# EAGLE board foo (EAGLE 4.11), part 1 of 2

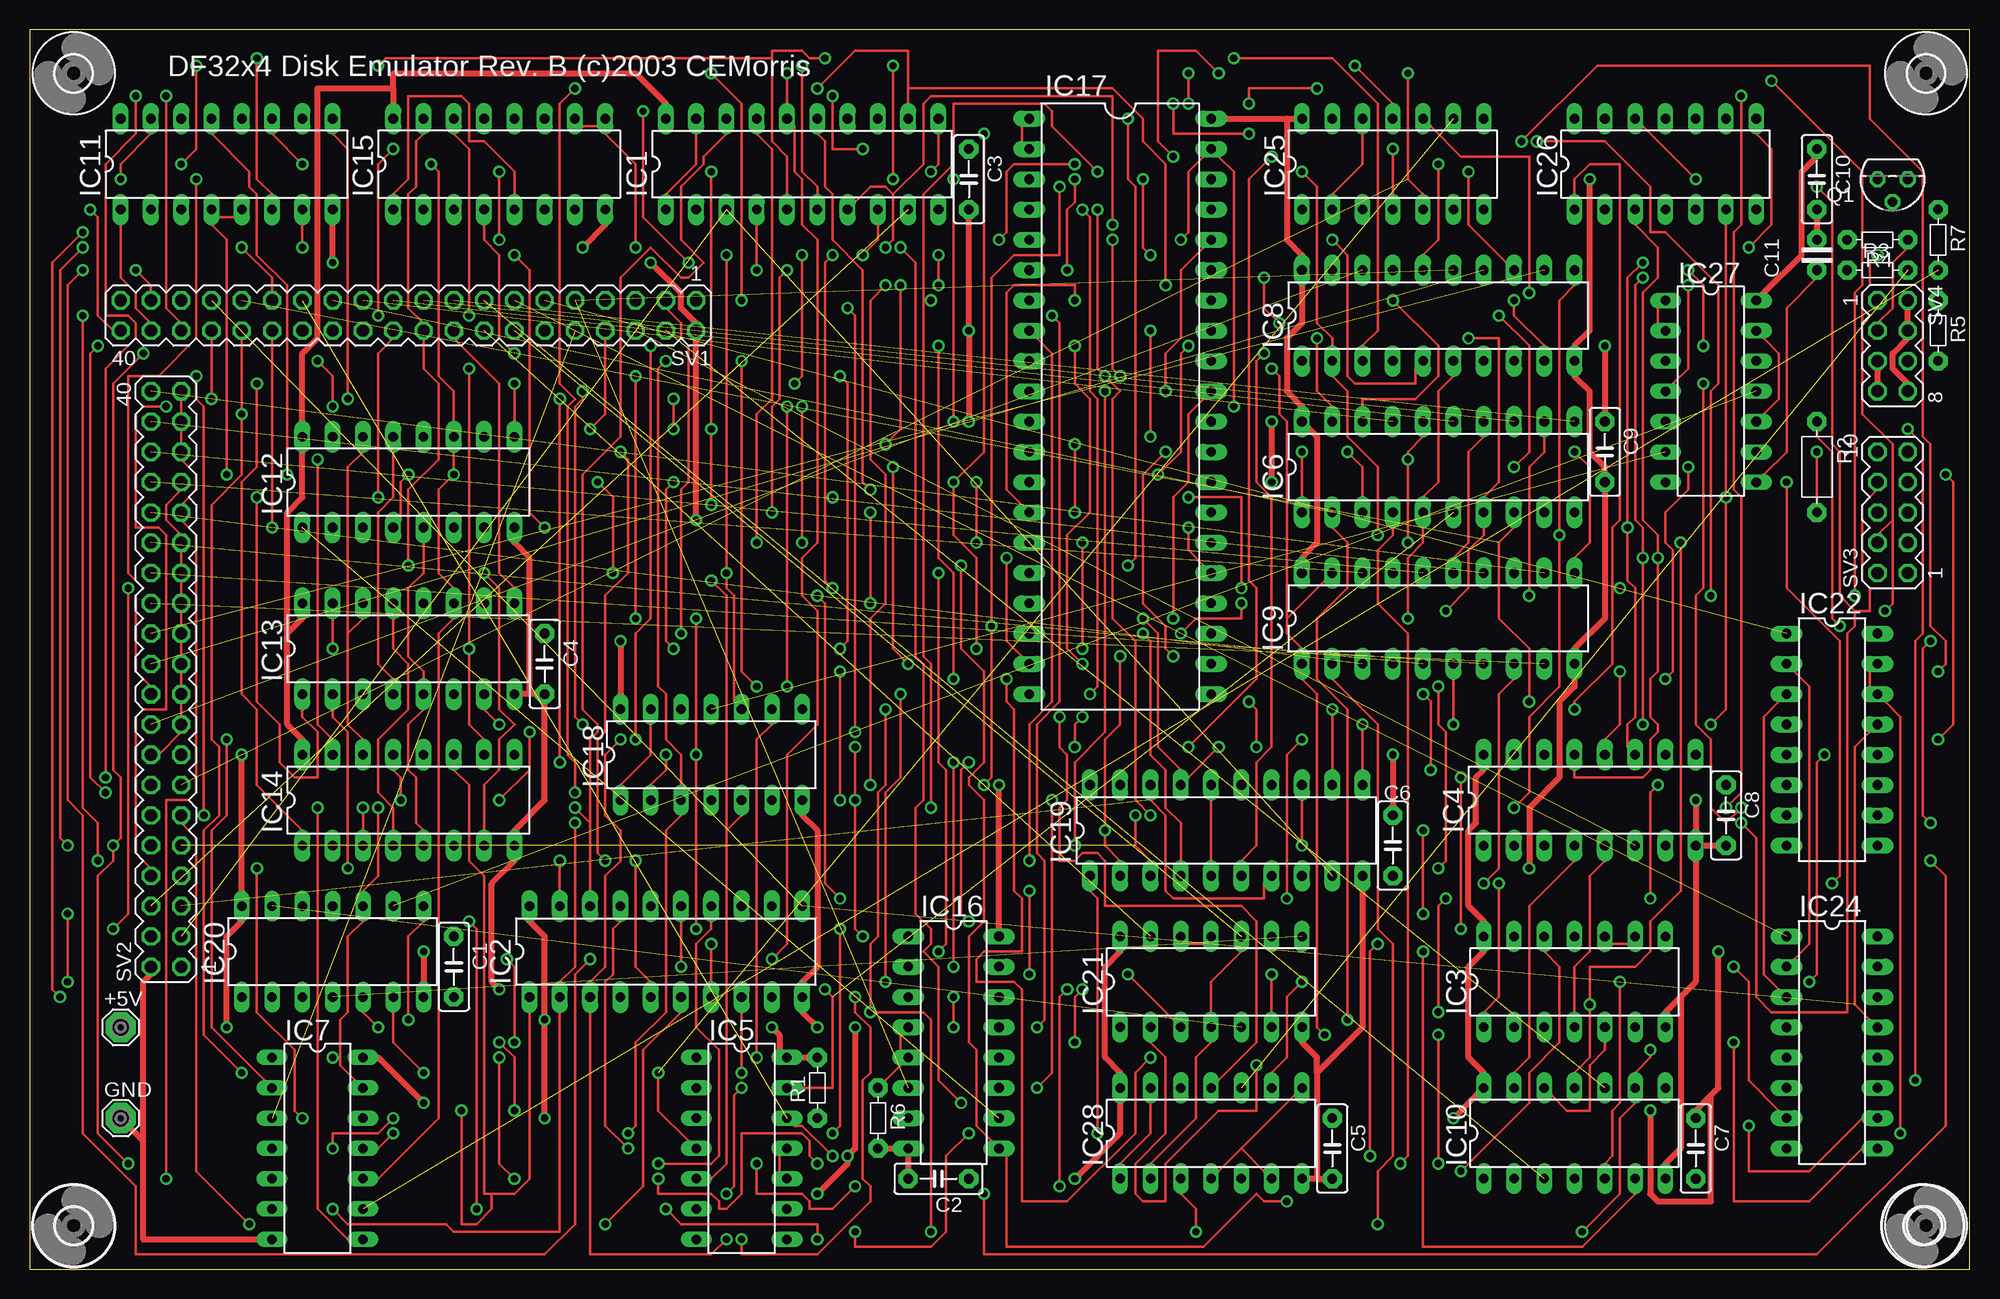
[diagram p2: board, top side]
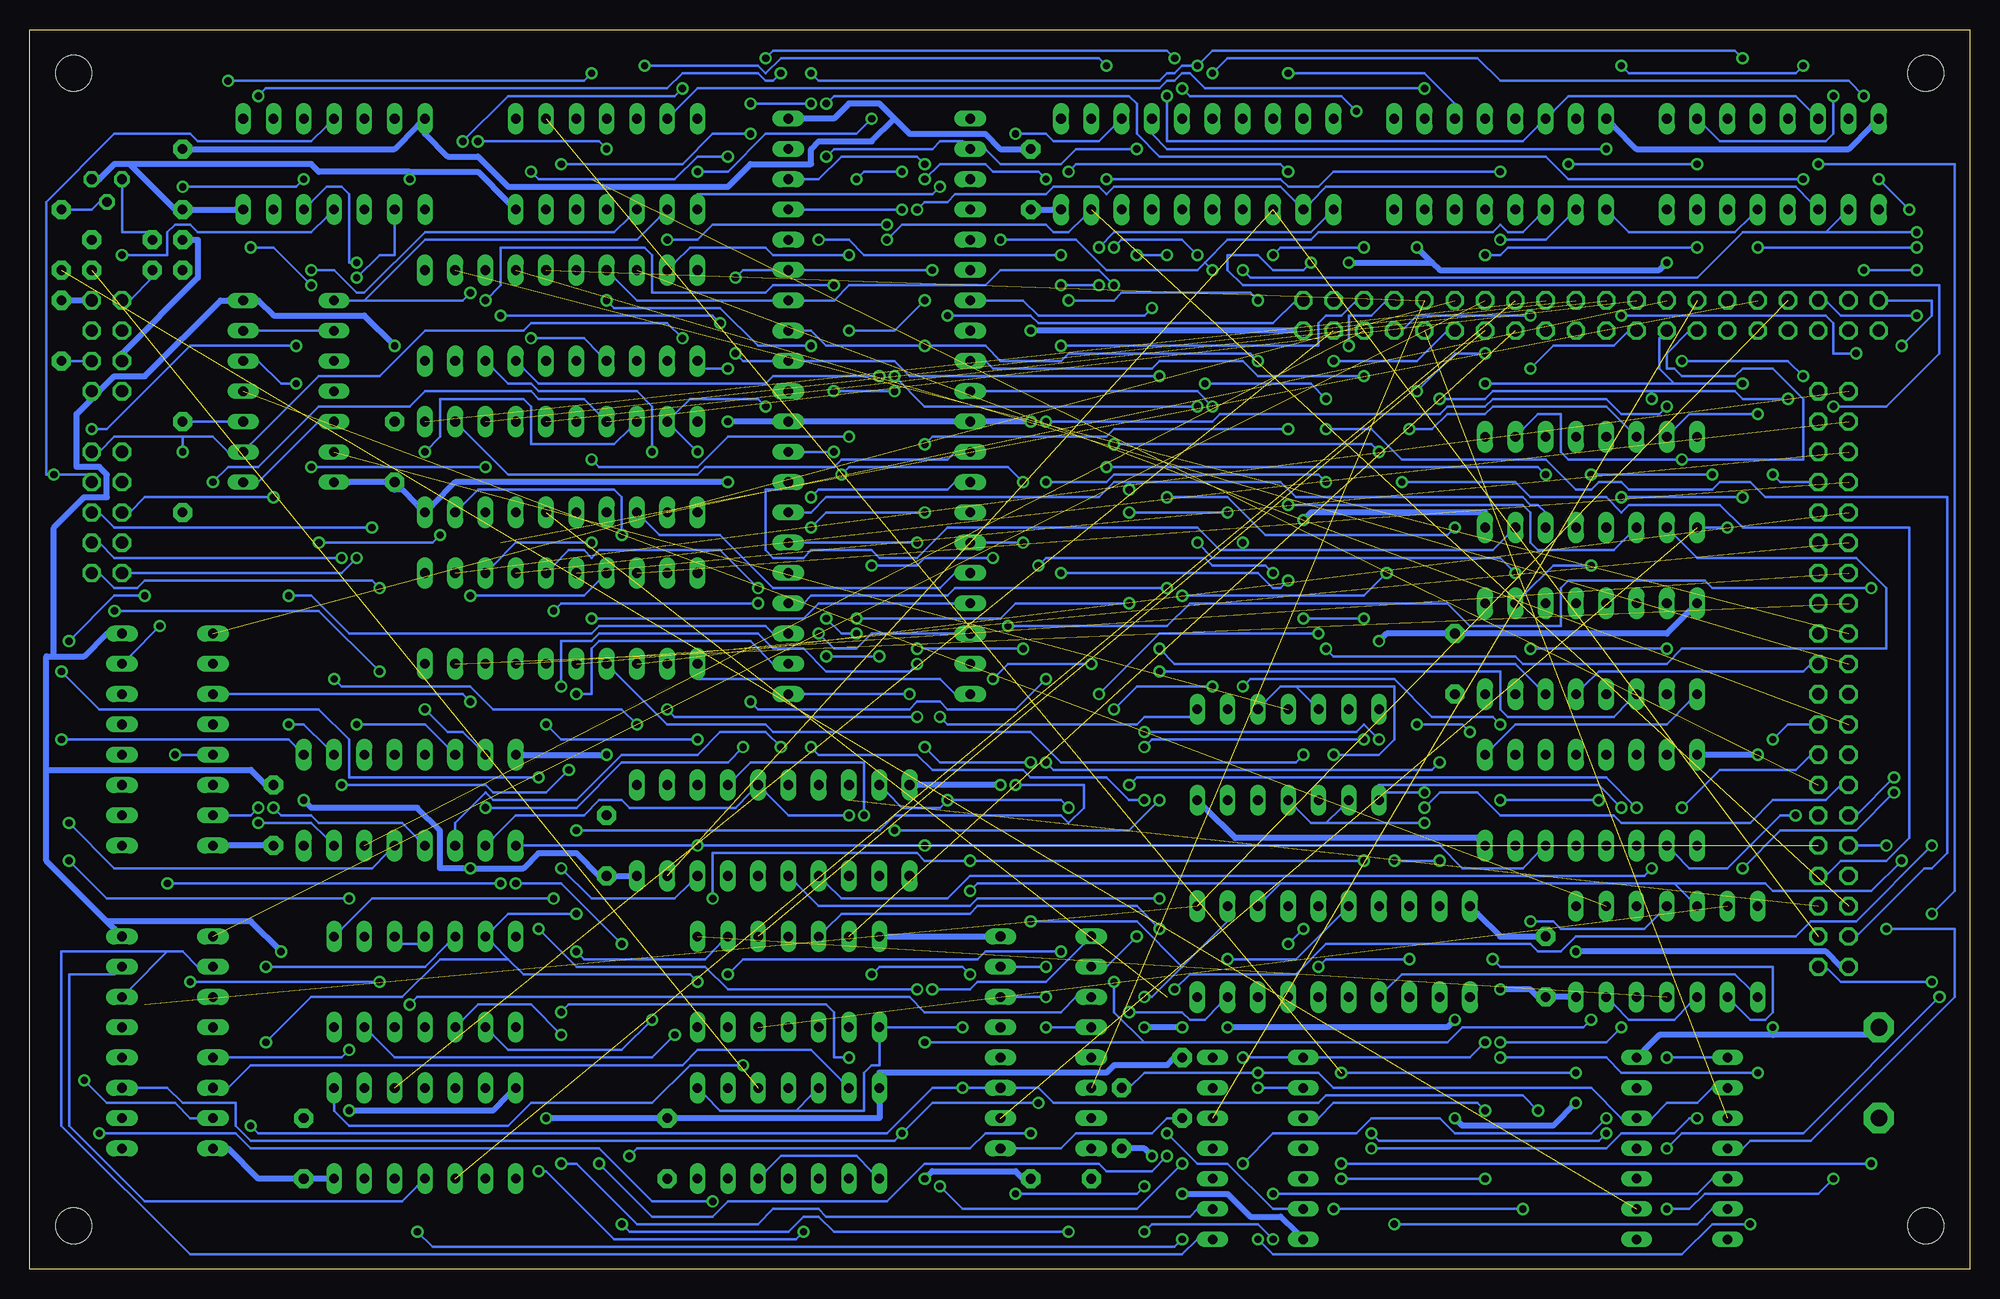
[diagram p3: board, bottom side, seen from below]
Size 162.67 x 103.94 mm. Coordinates in mm from the lower left corner, seen from the top.
Outline: 0,0 162.67,0 162.67,103.94 0,103.94 0,0
Copper layers (1*16): Top 0.035mm / dielectric 1.5mm / Bottom 0.035mm
Design rules "default": minimum track width 8mil, minimum drill 24mil, track to track 8mil, track to pad 8mil, pad to pad 8mil, via to via 8mil, smd to smd 8mil, copper to edge 40mil, drill to drill 8mil, minimum pad ring 10mil, minimum via ring 8mil, stop-mask expansion 4mil, vias tented up to drill 0mil, thermal gap 10mil
Net classes: 1 supply: width 0.508 mm

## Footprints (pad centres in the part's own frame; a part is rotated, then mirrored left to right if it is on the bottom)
SE14 = drill 1.397 pad 2.54 octagon: MP 0,0
C5B2.5 = drill 0.813 pad 1.6 octagon: 1 -2.54,0; 2 2.54,0
C-2,5 = drill 0.813 pad 1.6 octagon: 1 -1.27,0; 2 1.27,0
DIL20 = drill 0.813 long: 1 -11.43,-3.81; 2 -8.89,-3.81; 3 -6.35,-3.81; 4 -3.81,-3.81; 5 -1.27,-3.81; 6 1.27,-3.81; 7 3.81,-3.81; 8 6.35,-3.81; 9 8.89,-3.81; 10 11.43,-3.81; 11 11.43,3.81; 12 8.89,3.81; 13 6.35,3.81; 14 3.81,3.81; 15 1.27,3.81; 16 -1.27,3.81; 17 -3.81,3.81; 18 -6.35,3.81; 19 -8.89,3.81; 20 -11.43,3.81
DIL14 = drill 0.8 long: 1 -7.62,-3.81; 2 -5.08,-3.81; 3 -2.54,-3.81; 4 0,-3.81; 5 2.54,-3.81; 6 5.08,-3.81; 7 7.62,-3.81; 8 7.62,3.81; 9 5.08,3.81; 10 2.54,3.81; 11 0,3.81; 12 -2.54,3.81; 13 -5.08,3.81; 14 -7.62,3.81
DIL16 = drill 0.813 long: 1 -8.89,-3.81; 2 -6.35,-3.81; 3 -3.81,-3.81; 4 -1.27,-3.81; 5 1.27,-3.81; 6 3.81,-3.81; 7 6.35,-3.81; 8 8.89,-3.81; 9 8.89,3.81; 10 6.35,3.81; 11 3.81,3.81; 12 1.27,3.81; 13 -1.27,3.81; 14 -3.81,3.81; 15 -6.35,3.81; 16 -8.89,3.81
DIL40 = drill 0.813 long: 1 -24.13,-7.62; 2 -21.59,-7.62; 3 -19.05,-7.62; 4 -16.51,-7.62; 5 -13.97,-7.62; 6 -11.43,-7.62; 7 -8.89,-7.62; 8 -6.35,-7.62; 9 -3.81,-7.62; 10 -1.27,-7.62; 11 1.27,-7.62; 12 3.81,-7.62; 13 6.35,-7.62; 14 8.89,-7.62; 15 11.43,-7.62; 16 13.97,-7.62; 17 16.51,-7.62; 18 19.05,-7.62; 19 21.59,-7.62; 20 24.13,-7.62; 21 24.13,7.62; 22 21.59,7.62; 23 19.05,7.62; 24 16.51,7.62; 25 13.97,7.62; 26 11.43,7.62; 27 8.89,7.62; 28 6.35,7.62; 29 3.81,7.62; 30 1.27,7.62; 31 -1.27,7.62; 32 -3.81,7.62; 33 -6.35,7.62; 34 -8.89,7.62; 35 -11.43,7.62; 36 -13.97,7.62; 37 -16.51,7.62; 38 -19.05,7.62; 39 -21.59,7.62; 40 -24.13,7.62
TO92 = drill 0.813 octagon: 1 1.27,0; 2 0,1.905; 3 -1.27,0
R-5 = drill 0.813 pad 1.6 octagon: 1 -2.54,0; 2 2.54,0
R-7,5 = drill 0.813 pad 1.6 octagon: 1 -3.81,0; 2 3.81,0
MA20-2 = drill 1.016 octagon: 1 -24.13,-1.27; 2 -24.13,1.27; 3 -21.59,-1.27; 4 -21.59,1.27; 5 -19.05,-1.27; 6 -19.05,1.27; 7 -16.51,-1.27; 8 -16.51,1.27; 9 -13.97,-1.27; 10 -13.97,1.27; 11 -11.43,-1.27; 12 -11.43,1.27; 13 -8.89,-1.27; 14 -8.89,1.27; 15 -6.35,-1.27; 16 -6.35,1.27; 17 -3.81,-1.27; 18 -3.81,1.27; 19 -1.27,-1.27; 20 -1.27,1.27; 21 1.27,-1.27; 22 1.27,1.27; 23 3.81,-1.27; 24 3.81,1.27; 25 6.35,-1.27; 26 6.35,1.27; 27 8.89,-1.27; 28 8.89,1.27; 29 11.43,-1.27; 30 11.43,1.27; 31 13.97,-1.27; 32 13.97,1.27; 33 16.51,-1.27; 34 16.51,1.27; 35 19.05,-1.27; 36 19.05,1.27; 37 21.59,-1.27; 38 21.59,1.27; 39 24.13,-1.27; 40 24.13,1.27
MA05-2 = drill 1.016 octagon: 1 -5.08,-1.27; 2 -5.08,1.27; 3 -2.54,-1.27; 4 -2.54,1.27; 5 0,-1.27; 6 0,1.27; 7 2.54,-1.27; 8 2.54,1.27; 9 5.08,-1.27; 10 5.08,1.27
MA04-2 = drill 1.016 octagon: 1 -3.81,-1.27; 2 -3.81,1.27; 3 -1.27,-1.27; 4 -1.27,1.27; 5 1.27,-1.27; 6 1.27,1.27; 7 3.81,-1.27; 8 3.81,1.27
3,0 = hole 3: 0,0

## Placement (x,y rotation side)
+5V  SE14  [SE14]  7.62,20.28 0 top
C1  [C5B2.5]  35.55,25.36 270 top
C2  [C5B2.5]  76.2,7.58 180 top
C3  [C5B2.5]  78.73,91.4 270 top
C4  [C5B2.5]  43.17,50.76 270 top
C5  [C5B2.5]  109.22,10.12 270 top
C6  [C5B2.5]  114.3,35.52 270 top
C7  [C5B2.5]  139.69,10.12 270 top
C8  [C5B2.5]  142.24,38.06 270 top
C9  [C5B2.5]  132.08,68.54 270 top
C10  [C5B2.5]  149.86,91.4 270 top
C11  [C-2,5]  149.86,85.05 90 top
GND  SE14  [SE14]  7.62,12.66 0 top
IC1  74LS240N  [DIL20]  64.77,92.67 0 top
IC2  74LS244N  [DIL20]  53.34,26.63 0 top
IC3  74LS00N  [DIL14]  129.53,24.09 0 top
IC4  74LS138N  [DIL16]  130.81,39.33 0 top
IC5  74LS32N  [DIL14]  59.68,10.12 270 top
IC6  74LS244N  [DIL20]  118.11,67.27 0 top
IC7  74LS74N  [DIL14]  24.12,10.12 270 top
IC8  74LS240N  [DIL20]  118.11,79.97 0 top
IC9  74LS240N  [DIL20]  118.11,54.57 0 top
IC10  74LS04N  [DIL14]  129.53,11.39 0 top
IC11  74LS191N  [DIL16]  16.51,92.67 0 top
IC12  74LS191N  [DIL16]  31.75,66 0 top
IC13  74LS191N  [DIL16]  31.75,52.03 0 top
IC14  74LS191N  [DIL16]  31.75,39.33 0 top
IC15  74LS191N  [DIL16]  39.36,92.67 0 top
IC16  74LS191N  [DIL16]  77.47,19.01 270 top
IC17  DS1258  [DIL40]  91.44,72.35 270 top
IC18  74LS74N  [DIL14]  57.14,43.14 0 top
IC19  74LS240N  [DIL20]  100.33,36.79 0 top
IC20  74LS02N  [DIL14]  25.39,26.63 0 top
IC21  74LS01N  [DIL14]  99.06,24.09 0 top
IC22  74LS155N  [DIL16]  151.12,44.41 270 top
IC24  74LS155N  [DIL16]  151.12,19.01 270 top
IC25  74LS74N  [DIL14]  114.3,92.67 0 top
IC26  74LS30N  [DIL14]  137.16,92.67 0 top
IC27  74LS86N  [DIL14]  140.97,73.62 270 top
IC28  74LS07N  [DIL14]  99.06,11.39 0 top
Q1  2N3904  [TO92]  156.21,91.4 180 top
R1  1K  [R-5]  66.04,15.2 90 top
R2  1K  [R-7,5]  149.86,67.27 270 top
R3  220  [R-5]  154.94,83.78 0 top
R4  220  [R-5]  154.94,86.32 180 top
R5  220  [R-5]  160.02,78.7 270 top
R6  0  [R-5]  71.12,12.66 270 top
R7  4.7K  [R-5]  160.02,86.32 270 top
SV1  BUS1  [MA20-2]  31.75,79.97 180 top
SV2  BUS2  [MA20-2]  11.42,49.49 90 top
SV3  WRLOCK  [MA05-2]  156.21,63.46 90 top
SV4  PANEL LEDS  [MA04-2]  156.21,77.43 270 top
U$1  [3,0]  3.68,100.29 0 top
U$2  [3,0]  3.68,3.65 0 top
U$3  [3,0]  159,3.65 0 top
U$4  [3,0]  159,100.29 0 top

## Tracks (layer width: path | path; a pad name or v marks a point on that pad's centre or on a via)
0V  (via drill 0.61)
  Top 0.203: IC16.4 73.02,19.65 73.02,18.38 IC16.5 73.02,17.11 71.75,15.84 71.75,15.2 R6.1 | v77.47,20.28 v77.47,22.82 | v59.68,16.47 59.68,21.55 IC2.8 | IC11.5 17.14,88.23 15.87,88.23 IC11.4 15.23,87.59 16.51,86.32 v16.51,66.64 | IC15.5 40.63,90.13 40.63,92.04 38.09,94.58 36.82,94.58 36.82,97.75 36.19,98.39 31.75,98.39 31.75,91.4 30.48,90.13 IC15.1 | SV2.16 10.79,43.14 12.69,45.05 SV2.17 12.69,46.32 12.69,47.59 SV2.19 12.69,48.86 12.69,50.13 SV2.21 12.69,51.4 12.69,52.67 SV2.23 12.69,53.94 12.69,55.21 SV2.25 12.69,56.48 12.69,57.75 SV2.27 12.69,59.02 12.69,60.29 SV2.29 12.69,61.56 11.42,62.83 11.42,64.1 12.69,65.37 SV2.33 | IC14.5 33.02,36.79 32.38,37.43 32.38,41.24 31.75,41.87 31.75,45.68 33.02,46.95 IC13.5 33.02,49.49 33.02,50.13 31.75,51.4 31.75,57.11 33.02,58.38 33.02,60.92 IC12.5 | v16.51,44.41 16.51,38.06 15.23,36.79 15.23,20.28 19.68,15.84 IC7.2
  Bottom 0.203: v77.47,22.82 80.01,22.82 IC16.14 | v77.47,20.28 74.93,20.28 IC16.4 | IC7.2 21.59,15.2 22.86,13.93 25.39,13.93 26.67,12.66 IC7.12 29.21,12.66 31.75,15.2 53.34,15.2 54.6,16.47 v59.68,16.47 69.21,16.47 70.48,15.2 R6.1 | IC15.1 29.84,88.23 28.57,86.96 19.68,86.96 18.41,88.23 IC11.5 | SV2.21 13.33,50.76 13.96,50.13 31.11,50.13 32.38,48.86 IC13.5 | v16.51,66.64 15.87,66 13.33,66 SV2.33 | v16.51,44.41 15.23,45.68 13.33,45.68 SV2.17
660-663\
  Top 0.203: IC22.2 147.95,50.13 149.22,48.86 149.22,27.27 147.95,26 IC24.2
  Bottom 0.203: 151.12,26.63 149.86,26.63 148.59,25.36 IC24.2 | 151.12,26.63 160.02,26.63 160.02,12.03 149.22,1.23 66.04,1.23 64.77,2.5 IC5.8 | 151.12,26.63 154.3,23.46 IC24.14
(NED+EWL)\
  Bottom 0.203: IC20.1 18.41,23.46 19.68,24.73 47.62,24.73 48.89,23.46 IC2.4
ACBUS\0  (via drill 0.61)
  Top 0.203: v69.21,22.82 69.21,21.55 70.48,20.28 70.48,16.47 69.84,15.84 69.84,7.58 70.48,6.95 70.48,5.68 66.04,1.23 59.68,1.23 v59.68,2.5 | v18.41,3.77 13.96,8.22 13.96,36.16 12.69,37.43 SV2.11 | v109.22,46.95 109.22,41.87 IC19.12 | v88.26,46.32 87.62,45.68 v87.62,43.78 | v78.73,42.51 78.1,41.87 78.1,29.81 v78.73,29.17
  Bottom 0.203: 66.04,25.36 68.58,22.82 v69.21,22.82 | 66.04,25.36 62.22,29.17 IC2.12 | v59.68,2.5 58.41,1.23 24.12,1.23 21.59,3.77 v18.41,3.77 | v109.22,46.95 108.58,46.32 v88.26,46.32 | v87.62,43.78 86.36,42.51 v78.73,42.51 | v78.73,29.17 69.84,29.17 66.04,25.36
ACBUS\1  (via drill 0.61)  (1 unrouted)
  Top 0.203: v92.7,38.06 92.7,35.52 93.98,34.25 IC19.3
  Bottom 0.203: v92.7,38.06 92.7,42.51 102.23,42.51 103.5,41.24 IC19.14
ACBUS\2  (via drill 0.61)
  Top 0.203: IC19.5 99.06,34.25 99.06,39.33 IC19.16 | v47.62,66 48.89,64.73 v48.89,58.38 | v66.04,56.48 66.67,55.84 66.67,32.35 v67.94,31.08
  Bottom 0.203: v47.62,66 38.09,66 36.82,64.73 30.48,64.73 29.21,63.46 28.57,64.1 20.95,64.1 19.05,62.19 5.08,62.19 5.08,36.16 6.98,34.25 10.79,34.25 12.06,32.98 SV2.7 | v48.89,58.38 50.79,56.48 v66.04,56.48 | v67.94,31.08 83.18,31.08 83.81,30.44 96.52,30.44 98.42,32.35 IC19.5
ACBUS\3  (1 unrouted)
  Top 0.203: IC19.18 93.98,39.33 95.25,38.06 95.25,31.71 95.88,31.08 103.5,31.08 103.5,32.35 IC19.7
ACBUS\4  (2 unrouted)
ACBUS\5  (via drill 0.61)
  Top 0.203: v100.96,101.56 109.22,101.56 113.03,97.75 113.03,78.7 111.76,77.43 IC8.3 | v66.67,101.56 65.4,101.56 64.77,102.2 62.22,102.2 62.22,101.56 | 62.22,101.56 62.22,94.58 63.49,93.31 63.49,90.13 IC1.5 | v3.17,24.09 v3.17,29.81 | v12.69,92.67 13.96,93.94 v13.96,100.93 | v29.21,100.93 29.84,101.56 62.22,101.56
  Bottom 0.203: v100.96,101.56 100.33,102.2 67.31,102.2 v66.67,101.56 | v3.17,24.09 10.79,24.09 12.06,25.36 SV2.1 | v3.17,29.81 1.27,31.71 1.27,92.67 v12.69,92.67 | v13.96,100.93 14.6,100.29 28.57,100.29 v29.21,100.93
ACBUS\6  (via drill 0.61)
  Top 0.203: 72.39,90.13 71.75,90.77 70.48,90.77 69.21,89.5 IC1.7 | 72.39,90.13 74.93,92.67 74.93,97.75 75.56,98.39 90.8,98.39 v90.8,87.59 | v109.22,86.32 110.48,85.05 110.48,74.89 111.12,74.26 116.2,74.26 116.2,75.53 IC8.5 | v53.97,70.45 v53.97,72.99 | v64.13,74.26 64.77,74.89 v64.77,85.05 | v71.75,85.69 72.39,86.32 72.39,90.13
  Bottom 0.203: v90.8,87.59 105.41,87.59 106.68,86.32 v109.22,86.32 | v53.97,70.45 50.16,70.45 47.62,67.91 35.55,67.91 33.02,65.37 31.75,65.37 31.11,66 29.21,66 28.57,65.37 21.59,65.37 20.95,66 18.41,66 17.14,64.73 1.9,64.73 1.9,34.89 3.17,33.62 3.81,33.62 9.52,27.9 SV2.4 | v53.97,72.99 55.24,74.26 v64.13,74.26 | v64.77,85.05 66.04,86.32 71.12,86.32 v71.75,85.69
ACBUS\7  (via drill 0.61)  (1 unrouted)
  Top 0.203: v91.44,74.89 90.8,75.53 v90.8,86.32
  Bottom 0.203: v91.44,74.89 100.33,74.89 100.96,74.26 120.01,74.26 121.28,75.53 IC8.7 | v90.8,86.32 89.53,87.59 77.47,87.59 76.83,86.96 75.56,86.96 74.29,88.23 IC1.9
ACBUS\8  (via drill 0.61)
  Top 0.203: v124.45,81.24 124.45,79.97 127,77.43 IC8.9 | v95.25,82.51 95.25,92.67 93.34,94.58 93.34,96.48 90.8,99.02 73.66,99.02 | 73.66,99.02 73.66,97.75 IC1.12 | v11.42,72.35 9.52,72.35 8.88,71.72 8.88,62.19 10.79,62.19 11.42,61.56 11.42,46.95 9.52,46.95 8.88,46.32 8.88,34.89 10.15,33.62 SV2.8 | v55.24,84.42 51.43,88.23 v51.43,97.12 | v66.04,99.02 69.21,102.2 73.66,102.2 73.66,99.02
  Bottom 0.203: v124.45,81.24 123.19,82.51 123.19,85.69 111.12,85.69 110.48,85.05 110.48,81.88 100.96,81.88 100.33,82.51 v95.25,82.51 | v11.42,72.35 6.98,72.35 2.54,76.8 2.54,82.51 60.95,82.51 62.22,83.78 62.22,85.05 59.68,85.05 58.41,83.78 55.88,83.78 v55.24,84.42 | v51.43,97.12 52.7,98.39 65.4,98.39 v66.04,99.02
ACBUS\9  (via drill 0.61)
  Top 0.203: v52.7,8.85 57.14,8.85 57.78,9.49 57.78,18.38 55.88,20.28 55.88,27.27 57.14,28.54 57.14,29.17 IC2.14 | v8.25,8.85 5.71,11.39 5.71,32.98 6.98,34.25 v6.98,35.52 7.62,36.16 7.62,41.24 6.98,41.87 6.98,74.26 v9.52,76.8 | v30.48,93.94 29.21,92.67 v29.21,79.97
  Bottom 0.203: v8.25,8.85 v52.7,8.85 | v6.98,35.52 9.52,35.52 SV2.10 | v30.48,93.94 67.31,93.94 68.58,95.21 IC1.14 | v29.21,79.97 12.06,79.97 11.42,79.34 11.42,76.8 v9.52,76.8
ACBUS\10  (via drill 0.61)
  Top 0.203: v62.22,26 63.49,27.27 63.49,43.14 66.04,45.68 66.04,55.21 64.77,56.48 64.77,59.65 66.04,60.92 66.04,86.32 64.77,87.59 64.77,91.4 64.13,92.04 64.13,95.85 IC1.16 63.49,97.75 v63.49,100.29 | v6.34,41.24 6.34,75.53 8.88,78.07 8.88,79.34 8.25,79.97 6.34,79.97 6.34,92.67 8.88,95.21 v8.88,98.39
  Bottom 0.203: v62.22,26 56.51,26 52.7,29.81 IC2.16 | v6.34,41.24 9.52,38.06 SV2.12 | v8.88,98.39 10.15,99.66 39.36,99.66 41.27,101.56 62.22,101.56 v63.49,100.29
ACBUS\11  (via drill 0.61)
  Top 0.203: 46.98,37.43 46.98,31.71 IC2.18 | v45.71,38.7 46.98,37.43 | 46.98,37.43 46.98,44.41 47.62,45.05 47.62,45.68 46.35,46.95 46.35,66.64 49.52,69.81 49.52,83.15 52.06,85.69 54.6,83.15 55.24,83.15 56.51,84.42 54.6,86.32 54.6,90.77 56.51,92.67 56.51,93.31 58.41,95.21 IC1.18
  Bottom 0.203: v45.71,38.7 44.45,39.97 41.27,39.97 39.36,38.06 29.84,38.06 29.21,37.43 18.41,37.43 16.51,39.33 12.06,39.33 10.79,40.6 SV2.14
ACCLEAR\  (via drill 0.61)
  Top 0.203: 101.59,10.12 106.04,14.57 IC28.8 | 101.59,10.12 99.69,8.22 IC28.4 | 101.59,10.12 103.5,8.22 IC28.6 | v85.72,79.97 86.36,79.34 86.36,47.59 84.45,45.68 84.45,34.89 85.09,34.25 85.09,20.92 v84.45,20.28
  Bottom 0.203: 98.42,13.3 97.15,14.57 IC28.12 | 98.42,13.3 104.77,13.3 106.04,14.57 IC28.8 | 98.42,13.3 92.7,13.3 92.7,16.47 92.07,17.11 91.44,17.11 91.44,19.01 IC21.1 90.8,20.28 v84.45,20.28 | v85.72,79.97 78.73,79.97 78.1,79.34 58.41,79.34 56.51,81.24 SV1.1
BAC0
  Top 0.203: IC13.9 40.63,57.11 39.36,58.38 39.36,74.26 35.55,78.07 SV1.18
BAC1  (via drill 0.61)
  Top 0.203: v31.75,59.02 31.75,65.37 34.28,67.91 34.28,74.26 33.02,75.53 33.02,78.07 SV1.20 33.02,79.34 31.75,80.61 31.75,90.13 32.38,90.77 32.38,94.58 33.02,95.21 IC15.15
  Bottom 0.203: v31.75,59.02 34.92,59.02 37.46,56.48 IC13.10
BAC2  (via drill 0.61)
  Top 0.203: v29.21,64.73 29.21,76.8 30.48,78.07 SV1.22 | v19.05,64.73 19.05,47.59 20.95,45.68 20.95,42.51 22.22,41.24 24.12,41.24 24.12,45.05 22.86,46.32 22.86,46.95 IC13.1
  Bottom 0.203: IC14.9 40,43.78 38.09,45.68 25.39,45.68 23.49,47.59 IC13.1 | v19.05,64.73 v29.21,64.73
BAC3  (via drill 0.61)
  Top 0.203: v36.82,75.53 v36.82,52.03 36.82,45.68 38.09,44.41 IC14.10 | v25.39,52.03 25.39,54.57 IC13.15
  Bottom 0.203: v36.82,75.53 34.92,77.43 29.84,77.43 28.57,78.7 SV1.24 | v25.39,52.03 v36.82,52.03
BAC4  (via drill 0.61)
  Top 0.203: v19.05,74.26 19.05,67.27 17.78,66 17.78,48.22 19.05,46.95 19.05,40.6 22.86,36.79 IC14.1 | v40.63,74.26 40.63,71.08 IC12.9
  Bottom 0.203: v19.05,74.26 24.76,74.26 | 24.76,74.26 26.03,75.53 26.03,78.07 25.39,78.07 SV1.26 | 24.76,74.26 v40.63,74.26
BAC5  (via drill 0.61)
  Top 0.203: v24.12,67.91 24.12,45.68 25.39,44.41 IC14.15
  Bottom 0.203: IC12.10 37.46,70.45 36.19,71.72 34.28,71.72 34.28,68.54 33.65,67.91 v24.12,67.91 13.96,67.91 13.96,72.99 16.51,75.53 19.05,75.53 19.68,74.89 24.12,74.89 24.76,75.53 25.39,75.53 25.39,76.8 23.49,78.7 SV1.28
BAC6  (via drill 0.61)  (1 unrouted)
  Top 0.203: v20.32,62.19 20.32,78.07 SV1.30
  Bottom 0.203: v20.32,62.19 22.22,62.19 IC12.1
BAC7  (via drill 0.61)
  Top 0.203: v86.99,23.46 86.36,22.82 v86.36,6.95 | v66.04,8.85 65.4,9.49 65.4,10.76 64.77,11.39 59.68,11.39 59.68,6.31 58.41,5.04 57.78,5.04 57.78,5.68 57.14,6.31 52.7,6.31 v52.7,7.58 | v40.63,7.58 39.36,8.85 v39.36,17.74 | v17.78,16.47 14.6,19.65 14.6,36.79 15.87,38.06 15.87,43.78 15.23,44.41 15.23,64.1 17.78,66.64 v17.78,71.72 17.78,78.07 SV1.32
  Bottom 0.203: v86.99,23.46 83.81,23.46 83.18,24.09 77.47,24.09 74.29,27.27 IC16.1 | v86.36,6.95 84.45,5.04 69.84,5.04 v66.04,8.85 | v40.63,7.58 v52.7,7.58 | v39.36,17.74 30.48,17.74 29.21,16.47 v17.78,16.47 | v17.78,71.72 23.49,71.72 24.76,70.45 IC12.15
BAC8  (via drill 0.61)
  Top 0.203: v77.47,42.51 v77.47,25.36 | v44.45,42.51 v44.45,72.99 | v15.23,72.99 15.23,78.07 SV1.34 | v26.67,72.99 26.67,93.94 25.39,95.21 IC11.9
  Bottom 0.203: v77.47,25.36 80.01,25.36 IC16.15 | v77.47,42.51 76.83,41.87 45.08,41.87 v44.45,42.51 | v44.45,72.99 40.63,72.99 40,73.62 26.67,73.62 | 26.67,73.62 19.68,73.62 19.05,72.99 v15.23,72.99 | 26.67,73.62 v26.67,72.99
BAC9  (via drill 0.61)
  Top 0.203: v11.42,98.39 11.42,80.61 12.69,79.34 SV1.36
  Bottom 0.203: v11.42,98.39 11.42,95.21 12.06,94.58 20.95,94.58 22.22,95.85 IC11.10
BAC10
  Top 0.203: IC11.1 7.62,87.59 7.62,83.15 8.88,81.88 8.88,80.61 10.15,79.34 SV1.38
BAC11  (via drill 0.61)
  Top 0.203: v7.62,91.4 7.62,92.67 10.15,95.21 IC11.15 | v5.08,88.86 5.71,88.23 5.71,79.97 6.98,78.7 SV1.40
  Bottom 0.203: v5.08,88.86 v7.62,91.4
BADDAC\  (1 unrouted)
BBREAK\  (via drill 0.61)
  Top 0.203: 26.67,53.3 26.67,45.68 27.94,44.41 IC14.14 | 26.67,53.3 27.94,54.57 IC13.14 | 26.67,53.3 26.67,67.27 27.94,68.54 IC12.14 | IC10.13 124.45,16.47 125.73,17.74 125.73,30.44 129.53,34.25 IC4.4 | IC17.2 83.18,94.58 83.18,95.85 IC17.1 | v36.82,79.97 36.82,93.94 35.55,95.21 IC15.14 | v69.84,93.94 67.31,93.94 v67.31,98.39 | v142.24,38.7 143.5,39.97 143.5,64.73 142.87,65.37 142.87,86.96 143.5,87.59 v143.5,98.39 | v99.69,100.29 97.79,102.2 94.61,102.2 94.61,94.58 v95.88,93.31 | v46.98,70.45 48.25,71.72 48.25,78.07 SV1.8
  Bottom 0.203: IC11.14 13.33,97.12 14.6,98.39 33.65,98.39 34.92,97.12 IC15.14 36.19,95.85 37.46,94.58 67.31,94.58 v67.31,98.39 | v36.82,79.97 46.35,79.97 47.62,78.7 SV1.8 | v69.84,93.94 74.93,93.94 76.2,92.67 81.28,92.67 82.55,93.94 IC17.2 84.45,94.58 86.36,94.58 86.99,93.94 95.25,93.94 v95.88,93.31 | v142.24,38.7 141.6,38.06 139.06,38.06 138.43,37.43 131.44,37.43 130.17,36.16 IC4.4 | v143.5,98.39 142.87,99.02 109.22,99.02 107.95,100.29 101.59,100.29 100.96,99.66 100.33,99.66 v99.69,100.29 | v46.98,70.45 45.08,70.45 43.81,71.72 40.63,71.72 40,72.35 30.48,72.35 28.57,70.45 IC12.14
BIOP1  (1 unrouted)
BIOP2  (1 unrouted)
BIOP4  (1 unrouted)
BMB0  (1 unrouted)
BMB1  (1 unrouted)
BMB2  (1 unrouted)
BMB3  (via drill 0.61)  (1 unrouted)
  Top 0.203: v123.19,32.35 123.19,22.82 121.92,21.55 IC3.1 | v151.12,32.35 151.76,32.98 151.76,52.67 147.31,57.11 v147.31,66
  Bottom 0.203: v123.19,32.35 v151.12,32.35 | v147.31,66 146.05,67.27 143.5,67.27 138.43,72.35 130.81,72.35 129.53,73.62 120.65,73.62 120.01,72.99 116.2,72.99 114.93,71.72 IC6.17
BMB4  (via drill 0.61)  (1 unrouted)
  Top 0.203: v110.48,20.92 110.48,46.95 107.95,49.49 107.95,54.57 110.48,57.11 110.48,60.92 109.22,62.19 IC6.2
  Bottom 0.203: v110.48,20.92 113.03,18.38 122.55,18.38 123.82,19.65 IC3.2
BMB5  (via drill 0.61)  (1 unrouted)
  Top 0.203: v67.31,9.49 64.77,12.03 64.13,12.03 IC5.12 | v114.93,8.85 115.56,9.49 115.56,53.3 113.03,55.84 113.03,60.29 114.3,61.56 114.3,62.19 IC6.4
  Bottom 0.203: v67.31,9.49 68.58,8.22 72.39,8.22 73.02,8.85 87.62,8.85 90.8,5.68 104.14,5.68 105.41,4.41 110.48,4.41 v114.93,8.85
BMB6  (via drill 0.61)  (1 unrouted)
  Top 0.203: v66.67,23.46 67.31,22.82 67.31,15.2 64.77,15.2 IC5.13 | v3.17,35.52 2.54,36.16 2.54,83.78 v4.44,85.69 | v17.78,85.69 20.32,83.15 20.32,81.88 SV1.29
  Bottom 0.203: v66.67,23.46 65.4,24.73 56.51,24.73 53.97,27.27 36.82,27.27 36.19,26.63 34.28,26.63 33.02,27.9 14.6,27.9 13.33,29.17 9.52,29.17 v3.17,35.52 | v4.44,85.69 v17.78,85.69
BMB7  (via drill 0.61)  (1 unrouted)
  Top 0.203: IC24.3 146.68,23.46 145.41,24.73 145.41,46.32 146.68,47.59 IC22.3 | v125.73,47.59 125.73,52.03 123.19,54.57 123.19,60.92 124.45,62.19 IC6.8
  Bottom 0.203: v125.73,47.59 126.36,48.22 146.05,48.22 IC22.3
BMB8  (2 unrouted)
  Top 0.203: IC24.13 154.3,20.92 153.03,22.19 153.03,43.78 154.3,45.05 IC22.13
BMB9  (via drill 0.61)
  Top 0.203: v92.07,24.73 95.88,20.92 IC21.3 | v83.81,31.71 v83.81,24.73 | v4.44,79.97 4.44,38.7 5.71,37.43 v5.71,34.25
  Bottom 0.203: 24.76,32.35 23.49,31.08 IC20.12 | 24.76,32.35 57.78,32.35 | 57.78,32.35 59.05,31.08 IC2.13 | v92.07,24.73 91.44,25.36 84.45,25.36 v83.81,24.73 | v83.81,31.71 83.18,32.35 57.78,32.35 | v4.44,79.97 10.79,79.97 12.06,81.24 SV1.35 | v5.71,34.25 8.25,31.71 16.51,31.71 17.14,32.35 24.76,32.35
BMB10  (via drill 0.61)
  Top 0.203: v54.6,25.36 54.6,29.17 IC2.15 | v46.98,26 45.71,24.73 45.71,3.77 43.17,1.23 8.88,1.23 8.88,6.95 4.44,11.39 4.44,38.06 3.17,39.33 3.17,82.51 v4.44,83.78 | v8.88,83.78 10.15,82.51 10.15,81.88 SV1.37
  Bottom 0.203: v54.6,25.36 53.97,26 v46.98,26 | v4.44,83.78 v8.88,83.78
BMB11  (via drill 0.61)
  Top 0.203: v50.16,10.12 48.25,12.03 48.25,24.09 48.89,24.73 48.89,28.54 49.52,29.17 IC2.17 | v22.86,12.66 22.22,13.3 22.22,18.38 19.05,21.55 v19.05,33.62 | v6.34,39.97 5.08,41.24 5.08,76.8 v5.71,77.43
  Bottom 0.203: v50.16,10.12 30.48,10.12 29.21,11.39 24.76,11.39 23.49,12.66 v22.86,12.66 | v19.05,33.62 15.87,36.79 9.52,36.79 v6.34,39.97 | v5.71,77.43 3.17,79.97 3.17,81.24 6.98,81.24 SV1.39
BRK_RQ  (1 unrouted)
BRK_RQ\  (via drill 0.61)
  Top 0.203: v24.12,38.7 24.12,5.04 26.67,2.5 IC7.8
  Bottom 0.203: v24.12,38.7 20.95,41.87 14.6,41.87 13.33,43.14 SV2.15
BTS3  (1 unrouted)
BWCO\  (via drill 0.61)
  Top 0.203: v30.48,11.39 29.21,10.12 IC7.11 | v50.16,11.39 50.79,12.03 50.79,19.01 53.34,21.55 53.34,36.79 54.6,38.06 IC18.3 54.6,40.6 54.6,43.14 53.34,44.41 53.34,48.22 52.7,48.86 52.7,75.53 v53.34,76.16
  Bottom 0.203: v30.48,11.39 31.11,10.76 49.52,10.76 v50.16,11.39 | v53.34,76.16 46.35,76.16 43.81,78.7 SV1.12
DATA0\  (1 unrouted)
DATA1\  (via drill 0.61)
  Top 0.203: v118.11,92.67 118.11,86.32 116.84,85.05 IC8.16 | v102.23,95.21 95.88,95.21 v95.88,97.75 | v13.96,91.4 13.96,78.07 10.79,74.89 8.25,74.89 8.25,58.38 9.52,57.11 8.88,56.48 8.88,50.13 10.15,48.86 SV2.20
  Bottom 0.203: v118.11,92.67 107.95,92.67 105.41,95.21 v102.23,95.21 | v95.88,97.75 95.25,98.39 70.48,98.39 69.84,97.75 69.84,95.21 67.94,93.31 35.55,93.31 33.65,91.4 v13.96,91.4
DATA2\  (1 unrouted)
DATA3\  (1 unrouted)
DATA4\  (1 unrouted)
DATA5\  (1 unrouted)
DATA6\  (1 unrouted)
DATA7\  (1 unrouted)
DATA8\  (1 unrouted)
DATA9\  (1 unrouted)
DATA10\  (1 unrouted)
DATA11\  (1 unrouted)
DATA_IN  (via drill 0.61)  (1 unrouted)
  Top 0.203: IC3.4 129.53,21.55 129.53,25.36 130.81,26.63 130.81,32.98 132.08,34.25 IC4.5 | v115.56,100.29 115.56,91.4 116.84,90.13 IC25.5 | v146.05,99.66 153.66,92.04 153.66,82.51 153.03,81.88 v153.03,56.48 | v159.38,52.67 158.75,52.03 158.75,38.06 v159.38,37.43
  Bottom 0.203: v115.56,100.29 116.2,99.66 v146.05,99.66 | v153.03,56.48 155.57,56.48 v159.38,52.67 | v159.38,37.43 155.57,33.62 133.98,33.62 132.71,34.89 IC4.5
DISK_LED
  Top 0.203: SV4.3 154.94,79.34 156.21,80.61 156.21,84.42 157.47,85.69 R4.1
DMA0  (via drill 0.61)
  Top 0.203: v39.36,45.68 38.09,46.95 IC13.7 | v60.95,48.86 59.68,50.13 v59.68,76.16 | v118.11,33.62 118.74,34.25 118.74,45.05 118.11,45.68 v118.11,48.86 | v88.26,50.76 86.99,52.03 86.99,61.56 88.9,63.46 88.9,72.99 87.62,74.26 v87.62,77.43
  Bottom 0.203: v39.36,45.68 40,46.32 45.08,46.32 48.25,49.49 60.32,49.49 v60.95,48.86 | v59.68,76.16 60.32,76.8 75.56,76.8 76.2,76.16 81.28,76.16 82.55,77.43 v87.62,77.43 95.88,77.43 97.15,78.7 97.79,78.7 IC17.33 | v118.11,33.62 115.56,31.08 108.58,31.08 107.31,32.35 IC19.8 | v118.11,48.86 118.11,52.67 115.56,52.67 114.93,53.3 101.59,53.3 100.33,52.03 97.79,52.03 95.88,50.13 88.9,50.13 v88.26,50.76
DMA1  (via drill 0.61)
  Top 0.203: v67.94,52.03 68.58,52.67 68.58,74.26 v67.94,74.89 | v103.5,76.8 102.87,76.16 102.87,66 104.14,64.73 104.14,43.78 102.87,42.51 102.87,35.52 101.59,34.25 IC19.6
  Bottom 0.203: v67.94,52.03 66.67,50.76 38.09,50.76 36.19,48.86 IC13.6 | v67.94,74.89 88.9,74.89 90.17,76.16 97.79,76.16 IC17.32 100.33,76.16 102.87,76.16 v103.5,76.8
DMA2  (via drill 0.61)
  Top 0.203: v26.67,33.62 26.67,45.05 25.39,46.32 25.39,46.95 IC13.2 | v95.88,54.57 95.88,64.73 97.15,66 97.15,71.72 98.42,72.99 IC17.31 | v93.34,53.3 93.98,52.67 93.98,43.14 95.25,41.87 95.25,38.7 96.52,37.43 96.52,34.25 IC19.4
  Bottom 0.203: v26.67,33.62 27.3,32.98 83.81,32.98 85.72,31.08 94.61,31.08 95.88,32.35 IC19.4 | v95.88,54.57 94.61,53.3 v93.34,53.3
DMA3  (via drill 0.61)
  Top 0.203: v91.44,51.4 91.44,45.68 90.17,44.41 v90.17,36.79 90.17,35.52 91.44,34.25 IC19.2 | v95.88,51.4 95.25,52.03 95.25,53.94 93.34,55.84 93.34,66.64 v95.25,68.54 | v67.94,50.13 v67.94,39.33
  Bottom 0.203: v91.44,51.4 v95.88,51.4 | v95.25,68.54 97.79,68.54 IC17.29 | v67.94,50.13 39.36,50.13 39.36,46.95 38.73,46.32 29.84,46.32 28.57,47.59 IC13.3 | v67.94,39.33 70.48,36.79 v90.17,36.79
DMA4  (via drill 0.61)
  Top 0.203: v60.95,60.92 60.95,71.72 62.22,72.99 62.22,93.94 60.95,95.21 IC1.17
  Bottom 0.203: 60.95,60.29 62.86,60.29 64.77,62.19 85.72,62.19 88.26,59.65 91.44,59.65 92.07,60.29 97.15,60.29 97.79,59.65 100.33,59.65 100.96,60.29 100.96,65.37 99.69,65.37 IC17.28 | 60.95,60.29 40,60.29 38.73,61.56 IC12.7 | 60.95,60.29 v60.95,60.92
DMA5  (via drill 0.61)
  Top 0.203: v70.48,65.37 69.84,66 69.84,83.78 67.31,86.32 67.31,90.13 66.67,90.77 66.67,94.58 66.04,95.21 IC1.15
  Bottom 0.203: 70.48,66 71.75,66 73.02,64.73 95.88,64.73 97.15,63.46 97.79,63.46 IC17.27 | 70.48,66 57.78,66 56.51,64.73 37.46,64.73 36.82,64.1 36.19,64.1 35.55,63.46 IC12.6 | 70.48,66 v70.48,65.37
DMA6  (via drill 0.61)
  Top 0.203: v53.97,52.03 53.34,52.67 53.34,65.37 v53.97,66 | v80.01,95.21 80.01,68.54 v77.47,66 77.47,61.56 79.37,59.65 v79.37,52.03 | v88.26,52.03 v88.26,60.92
  Bottom 0.203: v53.97,52.03 53.34,51.4 38.09,51.4 37.46,50.76 25.39,50.76 24.12,52.03 6.98,52.03 6.98,57.11 9.52,59.65 22.86,59.65 24.76,61.56 IC12.2 | v53.97,66 54.6,66.64 71.75,66.64 72.39,66 v77.47,66 | v80.01,95.21 77.47,95.21 76.83,94.58 73.02,94.58 71.75,95.85 IC1.13 | v88.26,60.92 97.79,60.92 IC17.26 | v79.37,52.03 v88.26,52.03
DMA7  (via drill 0.61)
  Top 0.203: v57.14,92.04 v57.14,70.45 v57.14,64.1 | v75.56,92.04 76.2,92.67 76.2,95.21 IC1.11 | v97.15,62.19 97.15,60.29 98.42,59.02 IC17.25 | v87.62,69.18 v87.62,63.46
  Bottom 0.203: v57.14,64.1 37.46,64.1 36.82,63.46 36.82,60.92 36.19,60.29 29.84,60.29 28.57,61.56 IC12.3 | v57.14,92.04 57.78,92.67 74.93,92.67 v75.56,92.04 | v97.15,62.19 95.88,63.46 v87.62,63.46 | v87.62,69.18 86.99,69.81 72.39,69.81 71.75,70.45 v57.14,70.45
DMA8  (via drill 0.61)
  Top 0.203: v67.31,57.11 66.67,57.75 66.67,64.73 | 66.67,64.73 66.67,84.42 v67.31,85.05 | v69.84,85.05 71.12,86.32 71.12,87.59 IC1.8 | v22.86,85.69 22.86,87.59 IC11.7 | v40.63,85.05 41.9,83.78 41.9,63.46 v43.17,62.19 | v67.31,64.73 66.67,64.73
  Bottom 0.203: v67.31,57.11 85.09,57.11 85.72,56.48 97.15,56.48 97.79,55.84 IC17.24 | v67.31,85.05 v69.84,85.05 | v22.86,85.69 38.73,85.69 39.36,85.05 v40.63,85.05 | v43.17,62.19 43.81,61.56 59.05,61.56 62.22,64.73 v67.31,64.73
DMA9  (via drill 0.61)
  Top 0.203: v19.05,101.56 19.05,91.4 20.32,90.13 IC11.6 | v64.77,100.93 64.77,92.04 66.04,90.77 66.04,90.13 IC1.6 | v140.97,56.48 140.97,73.62 141.6,74.26 141.6,82.51 137.16,86.96 135.88,86.96 135.88,90.77 132.08,94.58 v126.36,94.58 | v107.95,99.02 102.23,99.02 v102.23,97.75 | v97.15,100.29 v97.15,97.75
  Bottom 0.203: v19.05,101.56 19.68,102.2 63.49,102.2 v64.77,100.93 66.04,100.93 66.67,100.29 67.31,100.29 67.94,99.66 96.52,99.66 v97.15,100.29 | v140.97,56.48 139.06,56.48 135.88,53.3 115.56,53.3 114.93,53.94 100.96,53.94 100.33,53.3 IC17.23 | v126.36,94.58 122.55,98.39 108.58,98.39 v107.95,99.02 | v97.15,97.75 v102.23,97.75
DMA10  (via drill 0.61)
  Top 0.203: v60.95,83.78 60.95,87.59 IC1.4 | v116.84,48.22 117.47,47.59 v117.47,41.87 | v136.52,40.6 135.88,39.97 v135.88,31.08 | v159.38,34.25 160.65,32.98 160.65,12.03 149.86,1.23 80.01,1.23 v80.01,6.31 | v69.21,6.95 67.31,5.04 65.4,5.04 65.4,5.68 64.77,6.31 60.95,6.31 v60.95,8.85 | v30.48,12.66 29.21,11.39 25.39,11.39 v25.39,10.12 | v2.54,22.82 1.9,23.46 1.9,84.42 v4.44,86.96
  Bottom 0.203: 12.06,86.96 10.79,88.23 IC11.2 | 12.06,86.96 19.05,86.96 22.86,83.15 60.32,83.15 v60.95,83.78 | v116.84,48.22 115.56,48.22 115.56,52.03 114.93,52.67 102.23,52.67 100.33,50.76 IC17.22 | v117.47,41.87 119.38,39.97 123.82,39.97 124.45,40.6 v136.52,40.6 | v135.88,31.08 156.21,31.08 v159.38,34.25 | v80.01,6.31 69.84,6.31 v69.21,6.95 | v60.95,8.85 58.41,11.39 51.43,11.39 50.16,12.66 44.45,12.66 43.17,11.39 31.75,11.39 v30.48,12.66 | v25.39,10.12 24.12,11.39 13.96,11.39 v2.54,22.82 | v4.44,86.96 12.06,86.96
DMA11  (via drill 0.61)
  Top 0.203: v88.9,48.22 89.53,48.86 89.53,72.99 88.9,73.62 88.9,88.23 v88.26,88.86
  Bottom 0.203: IC11.3 13.33,89.5 14.6,90.77 53.97,90.77 55.24,89.5 IC1.2 56.51,89.5 57.78,90.77 71.75,90.77 72.39,90.13 73.02,90.77 76.83,90.77 77.47,90.13 85.09,90.13 85.72,89.5 87.62,89.5 v88.26,88.86 | v88.9,48.22 97.79,48.22 IC17.21
DQ0  (via drill 0.61)
  Top 0.203: v81.91,59.65 81.91,52.67 83.18,51.4 IC17.19 | v92.07,59.02 92.7,59.65 92.7,90.77 92.07,91.4 v92.07,96.48 | v106.68,92.04 107.95,90.77 107.95,79.34 109.22,78.07 109.22,77.43 IC8.2 109.22,74.89 110.48,73.62 110.48,69.81 113.03,67.27 v113.03,61.56
  Bottom 0.203: v81.91,59.65 87.62,59.65 88.26,59.02 v92.07,59.02 | v92.07,96.48 93.34,95.21 100.96,95.21 104.14,92.04 v106.68,92.04 | v113.03,61.56 113.03,64.73 113.66,65.37 125.09,65.37 126.36,64.1 IC6.9
DQ1  (via drill 0.61)
  Top 0.203: v96.52,53.3 97.79,54.57 101.59,54.57 v101.59,55.84 | v118.74,55.21 120.65,57.11 120.65,60.29 121.92,61.56 121.92,62.19 IC6.7 121.92,64.73 123.19,66 123.19,78.07 v120.65,78.07
  Bottom 0.203: v96.52,53.3 95.25,52.03 93.34,52.03 92.07,53.3 85.09,53.3 IC17.18 | v101.59,55.84 118.11,55.84 v118.74,55.21 | v120.65,78.07 116.2,78.07 114.93,76.8 IC8.4
DQ2  (via drill 0.61)
  Top 0.203: v115.56,54.57 115.56,59.65 116.84,60.92 116.84,62.19 IC6.5 116.84,64.73 118.11,66 118.11,73.62 119.38,74.89 IC8.6
  Bottom 0.203: v115.56,54.57 97.79,54.57 96.52,55.84 85.09,55.84 IC17.17
DQ3  (via drill 0.61)
  Top 0.203: v110.48,68.54 111.76,67.27 111.76,64.73 IC6.3
  Bottom 0.203: IC17.16 85.09,58.38 86.36,57.11 100.33,57.11 104.77,61.56 109.85,61.56 111.12,62.83 IC6.3 | v110.48,68.54 110.48,72.35 111.76,73.62 120.01,73.62 120.65,74.26 122.55,74.26 123.82,75.53 IC8.8
DQ4  (via drill 0.61)
  Top 0.203: v129.53,68.54 130.81,67.27 130.81,60.92 129.53,59.65 IC9.11 | v79.37,60.92 v79.37,66 | v94.61,66.64 96.52,68.54 96.52,76.8 v97.15,77.43 | v114.3,81.24 118.11,77.43 118.11,74.89 116.2,72.99 111.76,72.99 111.76,72.35 IC6.18
  Bottom 0.203: v129.53,68.54 128.27,69.81 128.27,72.99 121.28,72.99 120.65,72.35 120.65,69.18 113.66,69.18 112.39,70.45 IC6.18 | v79.37,60.92 82.55,60.92 IC17.15 | v79.37,66 80.64,67.27 93.98,67.27 v94.61,66.64 | v97.15,77.43 101.59,77.43 104.77,80.61 113.66,80.61 v114.3,81.24
DQ5  (via drill 0.61)
  Top 0.203: v115.56,60.92 v115.56,67.91 115.56,68.54 116.84,69.81 IC6.16 | v87.62,81.24 87.62,82.51 82.55,82.51 81.91,81.88 81.91,65.37 83.18,64.1 IC17.14 | v93.98,78.7 v93.98,69.81
  Bottom 0.203: v115.56,60.92 121.92,60.92 123.82,59.02 IC9.13 | v87.62,81.24 90.17,78.7 v93.98,78.7 | v93.98,69.81 104.14,69.81 106.68,67.27 114.93,67.27 v115.56,67.91
DQ6  (via drill 0.61)
  Top 0.203: IC9.15 119.38,59.65 120.65,60.92 120.65,68.54 121.92,69.81 IC6.14 | v97.15,64.73 101.59,64.73 v101.59,57.11
  Bottom 0.203: v97.15,64.73 96.52,65.37 85.72,65.37 85.09,66 IC17.13 | v101.59,57.11 104.77,60.29 114.93,60.29 115.56,59.65 116.2,60.29 117.47,60.29 118.74,59.02 IC9.15
DQ7  (via drill 0.61)
  Top 0.203: v125.73,56.48 125.73,67.27 127,68.54 127,69.81 IC6.12
  Bottom 0.203: IC17.12 85.09,68.54 85.72,67.91 94.61,67.91 95.25,67.27 106.04,67.27 106.68,66.64 122.55,66.64 126.36,70.45 IC6.12 | v125.73,56.48 116.2,56.48 114.93,57.75 IC9.17
DQ8  (via drill 0.61)
  Top 0.203: v71.75,46.95 71.75,40.6 71.12,39.97 71.12,27.9 70.48,27.27 v70.48,21.55 74.93,21.55 75.56,20.92 v75.56,3.14 | v63.49,48.86 v63.49,72.35 | v113.03,3.77 113.03,8.22 114.3,9.49 114.3,27.27 113.03,28.54 113.03,45.68 109.22,49.49 IC9.2
  Bottom 0.203: v70.48,21.55 66.04,21.55 65.4,20.92 64.13,20.92 62.86,22.19 IC2.9 | v71.75,46.95 69.84,48.86 v63.49,48.86 | v63.49,72.35 64.77,73.62 82.55,73.62 IC17.10 | v113.03,3.77 112.39,3.14 99.06,3.14 97.79,4.41 96.52,4.41 95.25,3.14 v75.56,3.14
DQ9  (via drill 0.61)
  Top 0.203: v57.14,27.27 57.14,24.09 IC2.7 | v55.88,28.54 v55.88,43.14 v55.88,54.57 | v50.79,54.57 v50.79,74.89
  Bottom 0.203: v57.14,27.27 v55.88,28.54 | v55.88,43.14 56.51,42.51 76.2,42.51 78.73,45.05 100.33,45.05 100.96,45.68 109.22,45.68 113.66,50.13 IC9.4 | v50.79,74.89 59.68,74.89 60.95,76.16 67.94,76.16 68.58,75.53 81.91,75.53 82.55,76.16 IC17.9 | v55.88,54.57 v50.79,54.57
DQ10  (via drill 0.61)
  Top 0.203: v50.79,34.25 50.79,25.36 52.06,24.09 IC2.5 | v83.81,34.25 83.81,45.68 85.72,47.59 85.72,76.8 84.45,78.07 IC17.8 | v119.38,45.68 119.38,49.49 IC9.6 | v106.68,44.41 105.41,43.14 v105.41,31.08
  Bottom 0.203: v50.79,34.25 v83.81,34.25 87.62,34.25 88.26,34.89 105.41,34.89 v105.41,31.08 | v119.38,45.68 118.11,44.41 v106.68,44.41
DQ11  (via drill 0.61)
  Top 0.203: v49.52,44.41 48.25,43.14 48.25,38.06 49.52,36.79 49.52,34.25 48.25,32.98 48.25,25.36 46.98,24.09 IC2.3 46.98,21.55 46.98,1.23 57.14,1.23 v58.41,2.5 | v69.21,45.05 69.21,79.97 v68.58,80.61 | v121.92,32.35 123.19,33.62 123.19,48.22 124.45,49.49 IC9.8 | v113.03,27.27 112.39,26.63 v112.39,9.49 | v78.73,11.39 76.83,9.49 76.83,3.14 75.56,1.87 69.21,1.87 v69.21,3.14
  Bottom 0.203: v49.52,44.41 50.79,45.68 51.43,45.05 v69.21,45.05 | v68.58,80.61 69.21,79.97 78.1,79.97 79.37,81.24 82.55,81.24 IC17.7 | v121.92,32.35 118.11,32.35 v113.03,27.27 | v112.39,9.49 111.76,10.12 83.81,10.12 82.55,11.39 v78.73,11.39 | v69.21,3.14 68.58,3.77 59.68,3.77 v58.41,2.5
DRL  (via drill 0.61)
  Top 0.203: v58.41,6.31 59.05,6.95 59.05,14.57 v59.68,15.2
  Bottom 0.203: v58.41,6.31 22.86,6.31 21.59,7.58 IC7.5 | v59.68,15.2 57.14,15.2 IC5.2
DRL\  (via drill 0.61)
  Top 0.203: v48.25,3.77 51.43,6.95 51.43,18.38 54.6,21.55 IC2.6
  Bottom 0.203: v48.25,3.77 22.86,3.77 21.59,5.04 IC7.6
EA1  (via drill 0.61)
  Top 0.203: IC10.11 129.53,16.47 130.81,17.74 v130.81,22.19 130.81,25.36 134.62,25.36 135.88,26.63 135.88,29.17 138.43,31.71 v138.43,60.92 | IC8.11 129.53,82.51 128.27,81.24 v128.27,61.56 128.27,48.86 125.73,46.32 125.73,39.97 v124.45,38.7 | v76.2,77.43 76.2,59.65 77.47,58.38 v77.47,49.49 | v102.23,47.59 102.87,46.95 v102.87,43.78
  Bottom 0.203: v130.81,22.19 130.17,22.82 88.9,22.82 87.62,21.55 76.2,21.55 74.93,22.82 IC16.3 | v128.27,61.56 128.9,60.92 v138.43,60.92 | v76.2,77.43 54.6,77.43 54.6,79.34 53.97,79.97 52.7,79.97 51.43,81.24 SV1.5 | v77.47,49.49 80.01,46.95 85.72,46.95 86.36,47.59 88.26,47.59 88.9,46.95 101.59,46.95 v102.23,47.59 | v102.87,43.78 104.14,42.51 113.03,42.51 116.84,38.7 v124.45,38.7
EA2  (via drill 0.61)
  Top 0.203: v69.84,27.9 69.21,28.54 v69.21,39.33 v69.21,43.78 | v50.79,44.41 50.79,53.3 52.06,54.57 v52.06,77.43 | v120.65,92.04 120.65,87.59 123.82,84.42 IC8.13 | v104.14,93.31 102.23,91.4 102.23,57.75 102.87,57.11 102.87,49.49 v97.15,43.78
  Bottom 0.203: v69.84,27.9 72.39,25.36 IC16.2 | v69.21,43.78 68.58,44.41 v50.79,44.41 | v52.06,77.43 52.06,79.97 50.16,79.97 48.89,81.24 SV1.7 | v120.65,92.04 120.01,91.4 108.58,91.4 106.68,93.31 v104.14,93.31 | v97.15,43.78 96.52,43.14 88.26,43.14 86.99,41.87 79.37,41.87 78.73,41.24 72.39,41.24 70.48,39.33 v69.21,39.33
EA3  (2 unrouted)
EA\  (1 unrouted)
EMA1  (via drill 0.61)
  Top 0.203: v27.94,38.7 27.94,36.79 IC14.3 | v70.48,40.6 70.48,54.57 71.75,55.84 71.75,66.64 70.48,67.91 70.48,81.24 v71.75,82.51
  Bottom 0.203: v27.94,38.7 30.48,41.24 69.84,41.24 v70.48,40.6 | v71.75,82.51 73.02,83.78 81.28,83.78 82.55,82.51 93.98,82.51 95.25,81.24 97.79,81.24 IC17.34 100.33,81.24 111.76,81.24 113.66,83.15 IC8.17
EMA2  (via drill 0.61)
  Top 0.203: v14.6,38.06 14.6,72.35 13.96,72.99 v13.96,74.89 | v24.12,76.16 25.39,74.89 v25.39,72.35 | v77.47,71.08 v77.47,91.4 | v87.62,91.4 87.62,89.5 86.99,88.86 v86.99,83.78 | v111.76,45.68 111.76,41.87 IC19.11 | v137.16,49.49 137.79,50.13 137.79,60.29 137.16,60.92 137.16,63.46 139.06,65.37 v139.06,67.27 | v124.45,67.27 125.73,68.54 125.73,77.43 v123.19,79.97 | v104.77,79.34 103.5,80.61 v103.5,83.15
  Bottom 0.203: v14.6,38.06 15.87,38.06 20.32,33.62 23.49,33.62 24.76,34.89 IC14.2 | v13.96,74.89 15.23,76.16 v24.12,76.16 | v25.39,72.35 26.03,71.72 29.21,71.72 30.48,72.99 40,72.99 40.63,72.35 43.81,72.35 44.45,71.72 62.86,71.72 63.49,71.08 v77.47,71.08 | v77.47,91.4 78.1,92.04 81.91,92.04 82.55,92.67 86.36,92.67 v87.62,91.4 | v86.99,83.78 97.79,83.78 IC17.35 100.33,83.78 102.87,83.78 v103.5,83.15 | v111.76,45.68 113.03,46.95 123.82,46.95 125.73,48.86 136.52,48.86 v137.16,49.49 | v124.45,67.27 v139.06,67.27 | v123.19,79.97 105.41,79.97 v104.77,79.34
EMA3  (via drill 0.61)
  Top 0.203: v106.68,35.52 106.68,39.33 IC19.13 | v95.25,73.62 95.25,76.8 96.52,78.07 96.52,83.78 98.42,85.69 IC17.36 | v90.17,73.62 90.17,45.05 87.62,42.51 v87.62,35.52
  Bottom 0.203: IC14.6 36.19,34.89 37.46,33.62 42.54,33.62 44.45,35.52 v87.62,35.52 v106.68,35.52 121.28,35.52 IC4.1 | v90.17,73.62 v95.25,73.62
EMA4  (via drill 0.61)
  Top 0.203: v38.09,58.38 39.36,57.11 39.36,46.95 40.63,45.68 39.36,44.41 39.36,41.87 38.09,40.6 38.09,36.79 IC14.7 | v64.77,60.92 v64.77,72.35 | v89.53,88.86 89.53,75.53 v90.17,74.89 91.44,73.62 90.8,72.99 90.8,54.57 92.7,52.67 92.7,39.33 v93.98,38.06
  Bottom 0.203: IC4.2 123.82,36.16 121.92,38.06 116.2,38.06 114.93,39.33 113.03,39.33 112.39,38.7 103.5,38.7 102.23,39.97 IC19.15 100.96,39.97 99.06,38.06 v93.98,38.06 | v38.09,58.38 39.36,59.65 63.49,59.65 v64.77,60.92 | v64.77,72.35 87.62,72.35 v90.17,74.89 | v89.53,88.86 97.79,88.86 IC17.37
EMA5  (via drill 0.61)
  Top 0.203: v99.69,43.78 97.15,41.24 IC19.17 96.52,41.87 94.61,43.78 94.61,53.3 v93.34,54.57 | v81.28,86.32 81.91,86.96 81.91,92.04 82.55,92.67 v87.62,92.67 | v70.48,63.46 v70.48,55.84 | v62.22,63.46 62.22,72.35 62.86,72.99 62.86,83.15 v63.49,83.78
  Bottom 0.203: v99.69,43.78 100.96,45.05 104.77,45.05 106.68,43.14 113.03,43.14 116.84,39.33 123.82,39.33 124.45,39.97 127,37.43 127,36.79 IC4.3 | 64.13,84.42 64.77,83.78 72.39,83.78 74.93,86.32 v81.28,86.32 | 64.13,84.42 62.22,86.32 55.24,86.32 54.6,86.96 40,86.96 39.36,87.59 38.73,86.96 37.46,86.96 36.19,88.23 IC15.3 | v87.62,92.67 88.26,93.31 94.61,93.31 96.52,91.4 97.79,91.4 IC17.38 | v93.34,54.57 81.28,54.57 80.01,55.84 v70.48,55.84 | v62.22,63.46 v70.48,63.46 | 64.13,84.42 v63.49,83.78
EWL  (via drill 0.61)
  Top 0.203: v40,26 40.63,25.36 v40.63,19.01 | v60.95,17.74 60.95,44.41 62.22,45.68 IC18.9
  Bottom 0.203: v40,26 39.36,25.36 16.51,25.36 16.51,21.55 17.14,20.92 18.41,20.92 19.68,22.19 IC20.2 | v40.63,19.01 41.9,17.74 54.6,17.74 IC5.1 57.14,17.74 v60.95,17.74
EWL\  (via drill 0.61)
  Top 0.203: v86.36,46.32 86.36,43.78 86.99,43.14 86.99,39.33 86.36,38.7 86.36,34.25 87.62,34.25 88.26,34.89 89.53,34.89 90.17,34.25 90.17,30.44 101.59,30.44 102.87,29.17 102.87,19.01 99.69,15.84 IC28.11
  Bottom 0.203: v86.36,46.32 85.72,45.68 69.84,45.68 69.21,46.32 65.4,46.32 IC18.8
EWLSET  (1 unrouted)
GND  (via drill 0.61)
  Top 0.508: 138.43,22.82 139.69,24.09 139.69,34.25 IC4.8 | 138.43,22.82 137.16,21.55 IC3.7 | C8.2 141.6,35.52 140.33,35.52 IC4.8 | 138.43,22.82 138.43,10.12 137.16,8.85 IC10.7 | 107.95,7.58 108.58,7.58 C5.2 | 107.95,7.58 107.31,7.58 IC28.7 | 107.95,16.47 107.95,7.58 | 107.95,16.47 107.95,17.74 106.68,19.01 IC21.7 | 107.95,16.47 111.76,20.28 111.76,31.71 IC19.10 | SV4.7 154.94,74.26 154.94,75.53 SV4.5 | C11.2 149.86,86.96 149.86,88.23 C10.2 | v130.81,91.4 130.81,78.7 129.53,77.43 IC8.10 129.53,74.89 130.81,73.62 130.81,68.54 132.08,67.27 132.08,66.64 C9.2 132.08,65.37 132.08,54.57 129.53,52.03 IC9.10 129.53,49.49 129.53,48.86 128.27,47.59 128.27,41.24 125.73,38.7 v125.73,33.62 | v139.69,39.33 139.69,36.79 IC4.8 | v78.73,71.08 v78.73,78.7 78.73,88.23 C3.2 | v25.39,84.42 25.39,87.59 IC11.8 | v46.35,85.69 48.25,87.59 IC15.8 | v52.06,84.42 54.6,81.88 54.6,80.61 55.88,79.34 SV1.2 55.88,78.07 v55.88,62.83 | 9.52,10.76 9.52,2.5 19.05,2.5 IC7.7 | 9.52,10.76 8.25,12.03 GND.MP | 9.52,10.76 9.52,24.09 10.15,24.73 SV2.2 | v66.04,6.31 68.58,8.85 v68.58,9.49 69.21,10.12 v69.21,20.28 | R6.2 71.75,10.12 72.39,10.12 IC16.8 73.66,9.49 73.66,8.22 C2.2 | IC18.7 64.77,38.06 66.04,36.79 66.04,25.36 64.77,24.09 IC2.10 64.77,21.55 v66.04,20.28 | 41.9,48.22 42.54,48.22 C4.2 43.17,47.59 43.17,39.33 40.63,36.79 IC14.8 40.63,34.25 38.73,32.35 38.73,24.09 v39.36,23.46 | 41.9,48.22 41.27,48.22 IC13.8 | 41.9,48.22 41.9,59.65 40.63,60.92 IC12.8 | v33.02,26.63 33.02,24.09 IC20.7 | v104.14,71.08 v104.14,66
  Bottom 0.508: IC10.7 137.79,7.58 139.06,7.58 C7.2 140.33,7.58 143.5,7.58 146.05,10.12 IC24.8 | IC22.8 146.05,35.52 142.87,35.52 C8.2 | IC19.10 112.39,32.98 113.66,32.98 C6.2 114.93,32.98 116.84,34.89 120.01,34.89 121.28,33.62 v125.73,33.62 128.27,33.62 128.27,36.79 130.17,38.7 139.06,38.7 v139.69,39.33 | IC27.7 135.88,66 132.71,66 C9.2 132.08,65.37 131.44,65.37 130.17,64.1 IC6.10 128.9,64.1 127,66 v104.14,66 | IC26.7 145.41,88.86 149.22,88.86 C10.2 150.49,88.86 154.3,92.67 | SV4.5 154.94,76.8 148.59,83.15 148.59,86.32 149.22,86.32 C11.2 | 130.81,92.04 138.43,92.04 139.06,92.67 154.3,92.67 | 130.81,92.04 125.09,92.04 122.55,89.5 IC25.7 | 154.3,92.67 155.57,92.67 156.84,91.4 Q1.3 | v130.81,91.4 130.81,92.04 | IC1.10 76.83,88.86 78.1,88.86 C3.2 | v78.73,71.08 82.55,71.08 IC17.11 85.09,71.08 97.79,71.08 IC17.30 100.33,71.08 v104.14,71.08 | v25.39,84.42 26.03,83.78 44.45,83.78 45.08,84.42 | 45.08,84.42 v46.35,85.69 | v52.06,84.42 45.08,84.42 | v78.73,78.7 56.51,78.7 SV1.2 | v66.04,6.31 62.22,6.31 60.32,4.41 57.78,4.41 56.51,3.14 IC5.7 | v68.58,9.49 69.21,10.12 70.48,10.12 R6.2 | IC20.7 33.65,22.82 34.92,22.82 C1.2 36.19,22.82 36.82,23.46 v39.36,23.46 | IC18.7 64.13,38.7 61.59,36.16 41.27,36.16 IC14.8 | v66.04,20.28 v69.21,20.28 | v33.02,26.63 12.06,26.63 10.79,25.36 SV2.2 | v55.88,62.83 55.24,63.46 40.63,63.46 IC12.8
INT_RQ\  (1 unrouted)
IOP4\
  Bottom 0.203: IC10.4 130.17,6.95 131.44,5.68 153.03,5.68 159.38,12.03 159.38,24.73 155.57,24.73 IC24.15
IOS\  (1 unrouted)
  Top 0.203: IC28.2 93.98,8.85 97.79,12.66 97.79,17.74 99.06,19.01 IC21.4 99.06,21.55 99.06,24.09 101.59,26.63 IC21.10
IOT601  (1 unrouted)
IOT601\  (via drill 0.61)
  Top 0.203: v140.33,74.26 140.33,57.11 139.69,56.48 139.69,45.68 140.97,44.41 140.97,38.7 142.24,37.43 v143.5,38.7
  Bottom 0.203: v140.33,74.26 141.6,74.26 143.5,76.16 IC27.12 | v143.5,38.7 144.14,38.06 146.05,38.06 IC22.7
IOT602\  (via drill 0.61)
  Top 0.203: v97.79,3.14 97.79,5.04 96.52,6.31 IC28.3 | v120.01,8.22 125.73,13.93 125.73,16.47 128.27,19.01 128.27,25.36 127,26.63 IC3.12 | v139.06,83.78 140.33,82.51 v140.33,77.43 | v157.47,70.45 158.75,69.18 158.75,53.3 158.11,52.67 v158.11,15.84 | v142.87,25.36 144.14,24.09 144.14,15.84 146.68,13.3 IC24.7
  Bottom 0.203: v97.79,3.14 98.42,2.5 113.66,2.5 119.38,8.22 v120.01,8.22 | v139.06,83.78 137.16,83.78 135.25,81.88 134.62,81.88 129.53,86.96 113.66,86.96 112.39,88.23 IC25.3 | v140.33,77.43 149.22,77.43 156.21,70.45 v157.47,70.45 | v158.11,15.84 156.21,13.93 150.49,13.93 149.22,12.66 148.59,12.66 IC24.7 | v142.87,25.36 129.53,25.36 127.63,27.27 IC3.12
IOT604\  (via drill 0.61)
  Top 0.203: v106.68,24.09 105.41,22.82 105.41,17.74 104.14,16.47 IC28.9 | v142.87,19.01 142.87,5.68 149.22,5.68 153.66,10.12 IC24.9 | v6.98,28.54 8.25,29.81 v8.25,57.11 | v86.36,90.77 86.36,85.05 82.55,85.05 80.64,83.15 v80.64,53.94 80.64,41.24 v80.01,40.6 | v116.84,36.79 v116.84,29.81
  Bottom 0.203: v106.68,24.09 107.31,24.73 121.28,24.73 122.55,26 | 122.55,26 123.82,27.27 IC3.13 123.82,28.54 122.55,29.81 v116.84,29.81 | v142.87,19.01 139.06,22.82 131.44,22.82 128.27,26 122.55,26 | v6.98,28.54 1.27,28.54 1.27,22.82 13.33,10.76 18.41,10.76 19.05,10.12 IC7.4 | v8.25,57.11 21.59,57.11 22.22,57.75 33.65,57.75 34.28,57.11 34.28,53.94 41.9,53.94 43.81,55.84 65.4,55.84 67.31,53.94 v80.64,53.94 | v86.36,90.77 86.99,90.13 106.68,90.13 IC25.1 | v116.84,36.79 91.44,36.79 90.17,38.06 76.2,38.06 75.56,37.43 74.29,38.7 74.29,40.6 v80.01,40.6
IOT612\
  Top 0.203: IC28.1 91.44,8.85 93.98,11.39 93.98,13.93 IC28.13
  Bottom 0.203: IC28.5 100.96,8.22 99.69,9.49 93.34,9.49 92.07,8.22 IC28.1 | IC24.6 146.05,15.2 144.14,17.11 107.95,17.11 106.68,18.38 97.15,18.38 94.61,15.84 IC28.13
IOT614\  (via drill 0.61)
  Top 0.203: 38.73,6.31 38.09,6.31 38.09,32.98 36.82,34.25 36.82,40.6 35.55,41.87 IC14.11 | 38.73,6.31 40.63,6.31 41.9,7.58 41.9,21.55 IC2.1 | v84.45,15.2 85.72,16.47 v85.72,39.33 | v144.14,12.03 144.14,8.22 149.22,8.22 153.66,12.66 IC24.10 | v93.98,85.05 93.34,85.69 v93.34,91.4 | v89.53,92.04 85.72,95.85 85.72,97.12 85.09,97.75 77.47,97.75 77.47,92.67 74.93,90.13 74.93,81.24 | 74.93,81.24 74.93,51.4 75.56,50.76 v75.56,38.7 | v57.14,100.29 59.68,97.75 v59.68,81.24 | 74.93,81.24 v75.56,81.24 | 38.73,6.31 38.73,5.04 37.46,3.77 36.19,3.77 v36.19,13.3
  Bottom 0.203: IC19.19 90.8,39.97 89.53,38.7 86.36,38.7 v85.72,39.33 76.2,39.33 v75.56,38.7 | v144.14,12.03 143.5,11.39 90.8,11.39 86.99,15.2 v84.45,15.2 82.55,15.2 IC16.11 80.01,15.2 78.1,15.2 76.83,13.93 54.6,13.93 53.97,14.57 37.46,14.57 v36.19,13.3 | v93.98,85.05 100.33,85.05 100.96,85.69 107.31,85.69 108.58,84.42 IC8.19 | v93.34,91.4 92.7,92.04 v89.53,92.04 | v57.14,100.29 45.71,100.29 43.17,97.75 IC15.11 | v59.68,81.24 60.32,81.88 71.12,81.88 71.75,81.24 v75.56,81.24
IOT621  (via drill 0.61)
  Top 0.203: v116.84,26.63 116.84,1.87 130.17,1.87 134.62,6.31 IC10.6
  Bottom 0.203: v116.84,26.63 116.2,26 106.04,26 104.77,27.27 IC21.9
IOT621\  (via drill 0.61)
  Top 0.203: v133.34,24.09 133.34,13.93 132.71,13.3 132.71,9.49 132.08,8.85 IC10.5 | v149.22,24.09 149.86,24.73 149.86,42.51 v150.49,43.14
  Bottom 0.203: v133.34,24.09 v149.22,24.09 | v150.49,43.14 148.59,43.14 IC22.5
IOT622\  (via drill 0.61)
  Top 0.203: v135.88,18.38 135.88,17.74 134.62,16.47 IC10.9 134.62,13.93 133.34,12.66 133.34,6.31 v130.17,3.14 | v36.82,29.17 37.46,28.54 v37.46,5.04 | v53.34,5.04 54.6,3.77 66.04,3.77 v66.04,2.5
  Bottom 0.203: v135.88,18.38 136.52,17.74 146.05,17.74 IC24.5 | v36.82,29.17 34.92,29.17 34.28,28.54 27.3,28.54 26.03,29.81 IC20.11 | v37.46,5.04 v53.34,5.04 | v66.04,2.5 66.67,1.87 128.9,1.87 v130.17,3.14
IOT624\  (via drill 0.61)
  Top 0.203: IC1.1 53.34,90.13 55.88,92.67 55.88,95.21 IC1.19 | v89.53,11.39 89.53,31.08 88.9,31.71 IC19.1 | v73.02,85.69 74.29,84.42 74.29,51.4 74.93,50.76 74.93,39.33 74.29,38.7 74.29,29.81 75.56,28.54 75.56,27.27 74.93,26.63 76.2,25.36 76.2,15.84 v78.1,13.93
  Bottom 0.203: IC24.11 153.66,15.2 151.12,15.2 149.86,13.93 145.41,13.93 145.41,12.03 144.14,10.76 90.17,10.76 v89.53,11.39 86.99,13.93 v78.1,13.93 | v73.02,85.69 71.75,86.96 55.24,86.96 53.97,88.23 IC1.1
LAD
  Top 0.203: IC3.9 133.98,27.27 132.71,27.27 IC3.10
  Bottom 0.203: IC3.11 130.17,27.27 131.44,27.27 IC3.10
LAD\  (via drill 0.61)
  Top 0.203: IC7.10 29.21,7.58 34.28,12.66 34.28,53.3 35.55,54.57 IC13.11 35.55,57.11 34.28,58.38 34.28,65.37 v35.55,66.64 35.55,68.54 IC12.11 35.55,71.08 35.55,73.62 34.28,74.89 34.28,92.04 v33.65,92.67 | v118.74,31.08 118.11,30.44 v118.11,21.55 | v93.98,17.74 92.7,16.47 92.7,11.39 86.99,5.68 83.18,5.68 83.18,23.46 82.55,24.09 79.37,24.09 79.37,26 80.01,26.63 83.18,26.63 83.18,31.08 82.55,31.71 82.55,46.95 81.91,47.59 v81.91,49.49 | v73.66,50.76 72.39,52.03 v72.39,67.27 | v22.86,92.67 20.32,95.21 IC11.11
  Bottom 0.203: v118.74,31.08 133.98,31.08 136.52,28.54 IC3.8 | v118.11,21.55 117.47,22.19 95.88,22.19 95.25,21.55 95.25,17.74 v93.98,17.74 | v81.91,49.49 80.64,50.76 v73.66,50.76 | v72.39,67.27 36.19,67.27 v35.55,66.64 | v33.65,92.67 v22.86,92.67
N$1
  Top 0.203: C11.1 149.86,83.15 147.31,80.61 147.31,68.54 145.41,66.64 IC27.8
  Bottom 0.203: IC27.5 138.43,71.08 143.5,66 IC27.8
N$2  (via drill 0.61)
  Top 0.203: v67.31,11.39 67.94,12.03 v67.94,28.54 | IC21.11 98.42,27.27 97.15,27.27 IC21.12
  Bottom 0.203: v67.31,11.39 64.77,8.85 62.22,8.85 58.41,5.04 57.14,5.04 IC5.6 | v67.94,28.54 69.84,30.44 83.18,30.44 83.81,29.81 94.61,29.81 95.88,28.54 IC21.12
N$3  (1 unrouted)
N$4
  Top 0.203: IC10.12 127.63,14.57 128.9,13.3 130.81,13.3 130.81,17.11 132.08,18.38 132.08,19.01 IC3.5
N$5
  Bottom 0.203: Q1.1 154.94,90.77 154.94,86.96 152.4,86.96 R4.2
N$6
  Bottom 0.203: SV4.6 158.11,76.16 159.38,76.16 R5.2
N$10
  Top 0.203: IC14.4 30.48,36.79 30.48,38.7 29.21,39.97 29.21,44.41 31.75,46.95 31.75,50.76 30.48,52.03 30.48,54.57 IC13.13
N$11
  Top 0.203: IC13.4 30.48,49.49 29.21,50.76 29.21,63.46 30.48,64.73 30.48,68.54 IC12.13
N$12  (via drill 0.61)
  Top 0.203: v21.59,66.64 21.59,82.51 19.05,85.05 19.05,90.13 18.41,90.77 18.41,92.04 15.23,95.21 IC11.13 | v31.75,66.64 31.11,66 31.11,62.83 IC12.4
  Bottom 0.203: v21.59,66.64 v31.75,66.64
N$13  (via drill 0.61)
  Top 0.203: v118.11,8.85 v118.11,19.65
  Bottom 0.203: v118.11,8.85 116.84,8.85 111.76,3.77 101.59,3.77 100.33,5.04 96.52,5.04 95.88,4.41 65.4,4.41 64.77,5.04 IC5.9 | v118.11,19.65 120.65,22.19 125.09,22.19 126.36,20.92 IC3.3
N$14  (via drill 0.61)
  Top 0.203: v31.11,39.33 31.11,41.24 30.48,41.87 IC14.13 | v39.36,39.33 41.9,41.87 v41.9,45.05 | v46.35,45.68 45.71,46.32 45.71,72.35 46.35,72.99 v46.35,73.62 | v40.63,76.8 39.36,78.07 39.36,85.05 38.09,86.32 38.09,87.59 IC15.4
  Bottom 0.203: v31.11,39.33 v39.36,39.33 | v41.9,45.05 42.54,45.68 v46.35,45.68 | v46.35,73.62 43.17,76.8 v40.63,76.8
N$15
  Top 0.203: IC5.10 62.86,8.22 62.86,9.49 IC5.11
N$17  (1 unrouted)
N$19  (via drill 0.61)
  Top 0.203: v29.21,20.28 27.94,21.55 IC20.5 | v39.36,19.01 40.63,17.74 v40.63,13.3
  Bottom 0.203: v29.21,20.28 30.48,19.01 v39.36,19.01 | v40.63,13.3 41.27,13.93 53.34,13.93 54.6,12.66 IC5.3
N$21  (via drill 0.61)
  Top 0.203: v102.87,17.11 102.87,13.3 99.69,13.3 95.25,8.85 95.25,5.68 93.34,5.68 92.7,6.31 92.7,8.85 95.25,11.39 95.25,17.74 93.98,19.01 IC21.2
  Bottom 0.203: v102.87,17.11 107.31,17.11 110.48,13.93 120.65,13.93 122.55,12.03 135.88,12.03 137.16,13.3 137.16,13.93 IC10.8
N$22  (via drill 0.61)
  Top 0.203: v139.06,82.51 139.06,75.53 137.79,74.26 IC27.4 | v144.14,85.69 146.05,87.59 146.05,93.94 144.78,95.21 IC26.8
  Bottom 0.203: v139.06,82.51 142.24,85.69 v144.14,85.69
N$23
  Bottom 0.203: Q1.2 156.84,89.5 157.47,88.86 159.38,88.86 R7.1
NED  (via drill 0.61)  (1 unrouted)
  Top 0.203: v52.7,16.47 52.7,13.3 55.24,10.76 IC5.4 | v33.02,16.47 30.48,19.01 30.48,21.55 IC20.6
  Bottom 0.203: IC20.3 23.49,22.19 24.76,20.92 28.57,20.92 29.84,22.19 IC20.6 | v33.02,16.47 v52.7,16.47
NEDSET  (via drill 0.61)
  Top 0.203: v111.12,100.93 114.3,97.75 IC25.11 | v72.39,91.4 v72.39,100.93 | v39.36,86.32 v39.36,92.04
  Bottom 0.203: v111.12,100.93 101.59,100.93 100.96,100.29 99.69,101.56 73.02,101.56 v72.39,100.93 | v72.39,91.4 57.78,91.4 57.14,90.77 54.6,90.77 53.34,92.04 v39.36,92.04 | v39.36,86.32 35.55,86.32 33.65,88.23 IC15.2
NOERR  (1 unrouted)
OE\  (via drill 0.61)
